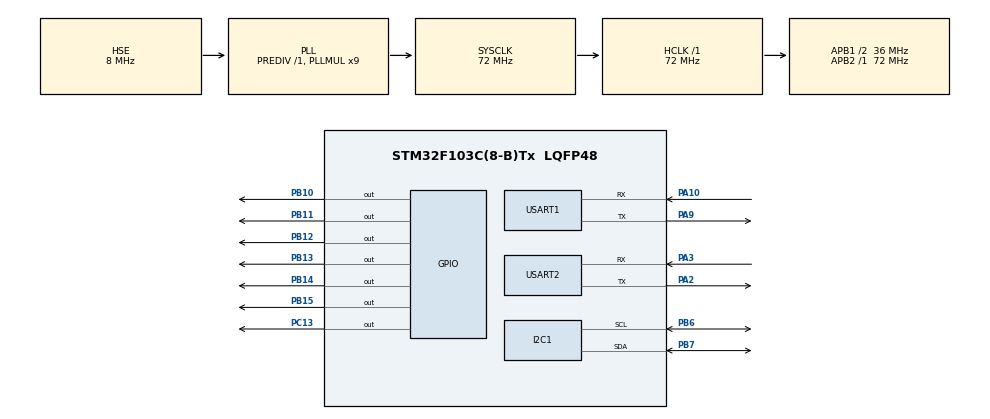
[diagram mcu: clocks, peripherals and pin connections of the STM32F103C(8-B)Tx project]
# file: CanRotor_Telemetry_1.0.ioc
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Dma.Request0=USART1_TX
Dma.Request1=USART1_RX
Dma.USART1_RX.1.Direction=DMA_PERIPH_TO_MEMORY
Dma.USART1_RX.1.Instance=DMA1_Channel5
Dma.USART1_RX.1.MemDataAlignment=DMA_MDATAALIGN_BYTE
Dma.USART1_RX.1.MemInc=DMA_MINC_ENABLE
Dma.USART1_RX.1.Mode=DMA_CIRCULAR
Dma.USART1_RX.1.PeriphDataAlignment=DMA_PDATAALIGN_BYTE
Dma.USART1_RX.1.PeriphInc=DMA_PINC_DISABLE
Dma.USART1_RX.1.Priority=DMA_PRIORITY_LOW
Dma.USART1_TX.0.Direction=DMA_MEMORY_TO_PERIPH
Dma.USART1_TX.0.Instance=DMA1_Channel4
Dma.USART1_TX.0.MemDataAlignment=DMA_MDATAALIGN_BYTE
Dma.USART1_TX.0.MemInc=DMA_MINC_ENABLE
Dma.USART1_TX.0.Mode=DMA_CIRCULAR
Dma.USART1_TX.0.PeriphDataAlignment=DMA_PDATAALIGN_BYTE
Dma.USART1_TX.0.PeriphInc=DMA_PINC_DISABLE
Dma.USART1_TX.0.Priority=DMA_PRIORITY_LOW
Mcu.Family=STM32F1
Mcu.Name=STM32F103C(8-B)Tx
Mcu.Package=LQFP48
NVIC.DMA1_Channel4_IRQn=true\:0\:0\:false\:false\:true\:false
NVIC.DMA1_Channel5_IRQn=true\:0\:0\:false\:false\:true\:false
NVIC.PriorityGroup=NVIC_PRIORITYGROUP_4
NVIC.USART1_IRQn=true\:0\:0\:false\:false\:true\:true
PA10.Mode=Asynchronous
PA10.Signal=USART1_RX
PA2.Mode=Asynchronous
PA2.Signal=USART2_TX
PA3.Mode=Asynchronous
PA3.Signal=USART2_RX
PA9.Mode=Asynchronous
PA9.Signal=USART1_TX
PB10.Signal=GPIO_Output
PB11.Signal=GPIO_Output
PB12.Signal=GPIO_Output
PB13.Signal=GPIO_Output
PB14.Signal=GPIO_Output
PB15.Signal=GPIO_Output
PB6.Mode=I2C
PB6.Signal=I2C1_SCL
PB7.Mode=I2C
PB7.Signal=I2C1_SDA
PC13-TAMPER-RTC.Signal=GPIO_Output
PD0-OSC_IN.Mode=HSE-External-Oscillator
PD0-OSC_IN.Signal=RCC_OSC_IN
PD1-OSC_OUT.Mode=HSE-External-Oscillator
PD1-OSC_OUT.Signal=RCC_OSC_OUT
ProjectManager.HeapSize=0x200
ProjectManager.StackSize=0x400
ProjectManager.TargetToolchain=MDK-ARM V5
RCC.AHBFreq_Value=72000000
RCC.APB1CLKDivider=RCC_HCLK_DIV2
RCC.APB1Freq_Value=36000000
RCC.APB1TimFreq_Value=72000000
RCC.APB2Freq_Value=72000000
RCC.APB2TimFreq_Value=72000000
RCC.HCLKFreq_Value=72000000
RCC.PLLMUL=RCC_PLL_MUL9
RCC.PLLSourceVirtual=RCC_PLLSOURCE_HSE
RCC.SYSCLKFreq_VALUE=72000000
RCC.SYSCLKSource=RCC_SYSCLKSOURCE_PLLCLK
RCC.USBFreq_Value=72000000
USART1.VirtualMode=VM_ASYNC
USART2.VirtualMode=VM_ASYNC
VP_SYS_VS_ND.Mode=No_Debug
board=CanRotor_Telemetry_1.0

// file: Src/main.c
/**
  ******************************************************************************
  * File Name          : main.c
  * Description        : Main program body
  ******************************************************************************
  ** This notice applies to any and all portions of this file
  * that are not between comment pairs USER CODE BEGIN and
  * USER CODE END. Other portions of this file, whether
  * inserted by the user or by software development tools
  * are owned by their respective copyright owners.
  *
  * COPYRIGHT(c) 2018 STMicroelectronics
  *
  * Redistribution and use in source and binary forms, with or without modification,
  * are permitted provided that the following conditions are met:
  *   1. Redistributions of source code must retain the above copyright notice,
  *      this list of conditions and the following disclaimer.
  *   2. Redistributions in binary form must reproduce the above copyright notice,
  *      this list of conditions and the following disclaimer in the documentation
  *      and/or other materials provided with the distribution.
  *   3. Neither the name of STMicroelectronics nor the names of its contributors
  *      may be used to endorse or promote products derived from this software
  *      without specific prior written permission.
  *
  * THIS SOFTWARE IS PROVIDED BY THE COPYRIGHT HOLDERS AND CONTRIBUTORS "AS IS"
  * AND ANY EXPRESS OR IMPLIED WARRANTIES, INCLUDING, BUT NOT LIMITED TO, THE
  * IMPLIED WARRANTIES OF MERCHANTABILITY AND FITNESS FOR A PARTICULAR PURPOSE ARE
  * DISCLAIMED. IN NO EVENT SHALL THE COPYRIGHT HOLDER OR CONTRIBUTORS BE LIABLE
  * FOR ANY DIRECT, INDIRECT, INCIDENTAL, SPECIAL, EXEMPLARY, OR CONSEQUENTIAL
  * DAMAGES (INCLUDING, BUT NOT LIMITED TO, PROCUREMENT OF SUBSTITUTE GOODS OR
  * SERVICES; LOSS OF USE, DATA, OR PROFITS; OR BUSINESS INTERRUPTION) HOWEVER
  * CAUSED AND ON ANY THEORY OF LIABILITY, WHETHER IN CONTRACT, STRICT LIABILITY,
  * OR TORT (INCLUDING NEGLIGENCE OR OTHERWISE) ARISING IN ANY WAY OUT OF THE USE
  * OF THIS SOFTWARE, EVEN IF ADVISED OF THE POSSIBILITY OF SUCH DAMAGE.
  *
  ******************************************************************************
  */
#include "main.h"
#include "Board.h"
#include "stm32f1xx_hal.h"

I2C_HandleTypeDef hi2c1;

UART_HandleTypeDef huart1;
UART_HandleTypeDef huart2;
DMA_HandleTypeDef hdma_usart1_tx;
DMA_HandleTypeDef hdma_usart1_rx;

/* USER CODE BEGIN PV */
/* Private variables ---------------------------------------------------------*/

uint8_t hours,minutes, seconds;

/* USER CODE END PV */

void SystemClock_Config(void);
static void MX_GPIO_Init(void);
static void MX_DMA_Init(void);
static void MX_I2C1_Init(void);
static void MX_USART1_UART_Init(void);
static void MX_USART2_UART_Init(void);

/* USER CODE BEGIN PFP */
/* Private function prototypes -----------------------------------------------*/

/* USER CODE END PFP */
extern volatile uint8_t rx_buffer[1];
char tmp[64];
uint32_t Option_Time = 0, System_Time = 0, Option_ref = 0;
uint32_t Request_Time = 0, Request_ref = 0;
/* USER CODE BEGIN 0 */
void HAL_GPIO_EXTI_Callback(uint16_t GPIO_Pin)
{

}
/* USER CODE END 0 */

int main(void)
{

  /* MCU Configuration----------------------------------------------------------*/

  /* Reset of all peripherals, Initializes the Flash interface and the Systick. */
  HAL_Init();

  /* Configure the system clock */
  SystemClock_Config();

  /* Initialize all configured peripherals */
  MX_GPIO_Init();
  MX_DMA_Init();
  MX_I2C1_Init();
  MX_USART1_UART_Init();
  MX_USART2_UART_Init();

  /* USER CODE BEGIN 2 */
	LCD_INIT();
  /* USER CODE END 2 */
  /* Infinite loop */
  /* USER CODE BEGIN WHILE */
	QueueCreate(UART1);
	//HAL_UART_Receive_DMA(&huart1, (uint8_t*)rx_buffer, 1);
	HAL_UART_Receive_IT(&huart1, (uint8_t*)rx_buffer, 1);

	LCD_XY(3, 0); LCD_PUTS((char *)"CAN_ROBOT_LAB");
 	LCD_XY(2, 1); LCD_PUTS((char *)"Can_Rotor  V1.0");
	LCD_XY(3, 2); LCD_PUTS((char *)"GCS-Telemetry");
	LCD_XY(6, 3); LCD_PUTS((char *)"QUAD-X");
	HAL_Delay(5000);
	LCD_CLEAR();

	Option_Time = micros();
  while (1)
  {
  /* USER CODE END WHILE */

	minutes = state.armedTime/60000000;
	seconds = ((state.armedTime)-minutes*60000000)/1000000;

	setInputFlags();
  resolveInputFlags();
 if((micros() - Option_Time) >= 300000){ //200ms
	  Option_ref = micros() - Option_Time;
	  Option_Time = micros();
	  //LED0_TOGGLE;

	printScreen();

	}
  /* USER CODE BEGIN 3 */
		//printf("%d\n\r", huart1.ErrorCode);
		SerialCom();
  }
  /* USER CODE END 3 */

}

/** System Clock Configuration
*/
void SystemClock_Config(void)
{

  RCC_OscInitTypeDef RCC_OscInitStruct;
  RCC_ClkInitTypeDef RCC_ClkInitStruct;

    /**Initializes the CPU, AHB and APB busses clocks
    */
  RCC_OscInitStruct.OscillatorType = RCC_OSCILLATORTYPE_HSE;
  RCC_OscInitStruct.HSEState = RCC_HSE_ON;
  RCC_OscInitStruct.HSEPredivValue = RCC_HSE_PREDIV_DIV1;
  RCC_OscInitStruct.HSIState = RCC_HSI_ON;
  RCC_OscInitStruct.PLL.PLLState = RCC_PLL_ON;
  RCC_OscInitStruct.PLL.PLLSource = RCC_PLLSOURCE_HSE;
  RCC_OscInitStruct.PLL.PLLMUL = RCC_PLL_MUL9;
  if (HAL_RCC_OscConfig(&RCC_OscInitStruct) != HAL_OK)
  {
    _Error_Handler(__FILE__, __LINE__);
  }

    /**Initializes the CPU, AHB and APB busses clocks
    */
  RCC_ClkInitStruct.ClockType = RCC_CLOCKTYPE_HCLK|RCC_CLOCKTYPE_SYSCLK
                              |RCC_CLOCKTYPE_PCLK1|RCC_CLOCKTYPE_PCLK2;
  RCC_ClkInitStruct.SYSCLKSource = RCC_SYSCLKSOURCE_PLLCLK;
  RCC_ClkInitStruct.AHBCLKDivider = RCC_SYSCLK_DIV1;
  RCC_ClkInitStruct.APB1CLKDivider = RCC_HCLK_DIV2;
  RCC_ClkInitStruct.APB2CLKDivider = RCC_HCLK_DIV1;

  if (HAL_RCC_ClockConfig(&RCC_ClkInitStruct, FLASH_LATENCY_2) != HAL_OK)
  {
    _Error_Handler(__FILE__, __LINE__);
  }

    /**Configure the Systick interrupt time
    */
  HAL_SYSTICK_Config(HAL_RCC_GetHCLKFreq()/1000);

    /**Configure the Systick
    */
  HAL_SYSTICK_CLKSourceConfig(SYSTICK_CLKSOURCE_HCLK);

  /* SysTick_IRQn interrupt configuration */
  HAL_NVIC_SetPriority(SysTick_IRQn, 0, 0);
}

/* I2C1 init function */
static void MX_I2C1_Init(void)
{

  hi2c1.Instance = I2C1;
  hi2c1.Init.ClockSpeed = 100000;
  hi2c1.Init.DutyCycle = I2C_DUTYCYCLE_2;
  hi2c1.Init.OwnAddress1 = 0;
  hi2c1.Init.AddressingMode = I2C_ADDRESSINGMODE_7BIT;
  hi2c1.Init.DualAddressMode = I2C_DUALADDRESS_DISABLE;
  hi2c1.Init.OwnAddress2 = 0;
  hi2c1.Init.GeneralCallMode = I2C_GENERALCALL_DISABLE;
  hi2c1.Init.NoStretchMode = I2C_NOSTRETCH_DISABLE;
  if (HAL_I2C_Init(&hi2c1) != HAL_OK)
  {
    _Error_Handler(__FILE__, __LINE__);
  }

}

/* USART1 init function */
static void MX_USART1_UART_Init(void)
{
  huart1.Instance = USART1;
  huart1.Init.BaudRate = 57600; //Telemetry
  huart1.Init.WordLength = UART_WORDLENGTH_8B;
  huart1.Init.StopBits = UART_STOPBITS_1;
  huart1.Init.Parity = UART_PARITY_NONE;
  huart1.Init.Mode = UART_MODE_TX_RX;
  huart1.Init.HwFlowCtl = UART_HWCONTROL_NONE;
  huart1.Init.OverSampling = UART_OVERSAMPLING_16;
  if (HAL_UART_Init(&huart1) != HAL_OK)
  {
    _Error_Handler(__FILE__, __LINE__);
  }
}

/* USART2 init function */
static void MX_USART2_UART_Init(void)
{

  huart2.Instance = USART2;
  huart2.Init.BaudRate = 57600; //CP2102
  huart2.Init.WordLength = UART_WORDLENGTH_8B;
  huart2.Init.StopBits = UART_STOPBITS_1;
  huart2.Init.Parity = UART_PARITY_NONE;
  huart2.Init.Mode = UART_MODE_TX_RX;
  huart2.Init.HwFlowCtl = UART_HWCONTROL_NONE;
  huart2.Init.OverSampling = UART_OVERSAMPLING_16;
  if (HAL_UART_Init(&huart2) != HAL_OK)
  {
    _Error_Handler(__FILE__, __LINE__);
  }

}

static void MX_DMA_Init(void)
{
  /* DMA controller clock enable */
  __HAL_RCC_DMA1_CLK_ENABLE();

  /* DMA interrupt init */
  /* DMA1_Channel4_IRQn interrupt configuration */
  HAL_NVIC_SetPriority(DMA1_Channel4_IRQn, 0, 0);
  HAL_NVIC_EnableIRQ(DMA1_Channel4_IRQn);
  /* DMA1_Channel5_IRQn interrupt configuration */
  HAL_NVIC_SetPriority(DMA1_Channel5_IRQn, 0, 0);
  HAL_NVIC_EnableIRQ(DMA1_Channel5_IRQn);

}

/** Configure pins as
        * Analog
        * Input
        * Output
        * EVENT_OUT
        * EXTI
        * Free pins are configured automatically as Analog (this feature is enabled through
        * the Code Generation settings)
*/
static void MX_GPIO_Init(void)
{

  GPIO_InitTypeDef GPIO_InitStruct;

  /* GPIO Ports Clock Enable */
  __HAL_RCC_GPIOC_CLK_ENABLE();
  __HAL_RCC_GPIOD_CLK_ENABLE();
  __HAL_RCC_GPIOA_CLK_ENABLE();
  __HAL_RCC_GPIOB_CLK_ENABLE();

  /*Configure GPIO pin Output Level */
  HAL_GPIO_WritePin(GPIOC, GPIO_PIN_13, GPIO_PIN_RESET);

  /*Configure GPIO pin Output Level */
  HAL_GPIO_WritePin(GPIOB, GPIO_PIN_10|GPIO_PIN_11|GPIO_PIN_12|GPIO_PIN_13
                          |GPIO_PIN_14|GPIO_PIN_15, GPIO_PIN_RESET);

  /*Configure GPIO pin : PC13 */
  GPIO_InitStruct.Pin = GPIO_PIN_13;
  GPIO_InitStruct.Mode = GPIO_MODE_OUTPUT_PP;
  GPIO_InitStruct.Speed = GPIO_SPEED_FREQ_LOW;
  HAL_GPIO_Init(GPIOC, &GPIO_InitStruct);

  /*Configure GPIO pins : PC14 PC15 */
  GPIO_InitStruct.Pin = GPIO_PIN_14|GPIO_PIN_15;
  GPIO_InitStruct.Mode = GPIO_MODE_ANALOG;
  HAL_GPIO_Init(GPIOC, &GPIO_InitStruct);

  /*Configure GPIO pins : PA0 PA1 PA8 PA11
                           PA12 PA13 PA14 PA15 */
  GPIO_InitStruct.Pin = GPIO_PIN_0|GPIO_PIN_1|GPIO_PIN_8|GPIO_PIN_11
                          |GPIO_PIN_12|GPIO_PIN_13|GPIO_PIN_14|GPIO_PIN_15;
  GPIO_InitStruct.Mode = GPIO_MODE_ANALOG;
  HAL_GPIO_Init(GPIOA, &GPIO_InitStruct);

		/*Configure GPIO pins : PA4 */
  GPIO_InitStruct.Pin = GPIO_PIN_4;
  GPIO_InitStruct.Mode = GPIO_MODE_IT_RISING_FALLING;
  GPIO_InitStruct.Pull = GPIO_NOPULL;
  HAL_GPIO_Init(GPIOA, &GPIO_InitStruct);

	/*Configure GPIO pins : PA5 PA6 PA7 */
  GPIO_InitStruct.Pin = GPIO_PIN_5|GPIO_PIN_6|GPIO_PIN_7;
  GPIO_InitStruct.Mode = GPIO_MODE_IT_RISING;
  GPIO_InitStruct.Pull = GPIO_NOPULL;
  HAL_GPIO_Init(GPIOA, &GPIO_InitStruct);

  /*Configure GPIO pins : PB1 PB2 PB3
                           PB4 PB5 PB8 PB9 */
  GPIO_InitStruct.Pin = GPIO_PIN_1|GPIO_PIN_2|GPIO_PIN_3
                          |GPIO_PIN_4|GPIO_PIN_5|GPIO_PIN_8|GPIO_PIN_9;
  GPIO_InitStruct.Mode = GPIO_MODE_ANALOG;
  HAL_GPIO_Init(GPIOB, &GPIO_InitStruct);

  /*Configure GPIO pins : PB0 PB10 PB11 PB12 PB13
                           PB14 PB15 */
  GPIO_InitStruct.Pin = GPIO_PIN_0|GPIO_PIN_10|GPIO_PIN_11|GPIO_PIN_12|GPIO_PIN_13
                          |GPIO_PIN_14|GPIO_PIN_15;
  GPIO_InitStruct.Mode = GPIO_MODE_OUTPUT_PP;
  GPIO_InitStruct.Speed = GPIO_SPEED_FREQ_LOW;
  HAL_GPIO_Init(GPIOB, &GPIO_InitStruct);

  /* EXTI interrupt init*/
  HAL_NVIC_SetPriority(EXTI4_IRQn, 1, 0);
  HAL_NVIC_EnableIRQ(EXTI4_IRQn);

  HAL_NVIC_SetPriority(EXTI9_5_IRQn, 1, 0);
  HAL_NVIC_EnableIRQ(EXTI9_5_IRQn);

}

void _Error_Handler(char * file, int line)
{
  while(1)
  {
  }
}

/************************ (C) COPYRIGHT STMicroelectronics *****END OF FILE****/
